# OR1 (OpenRule1um) technology LEF
# Aligned to drawn cell library: ML1-ML3 width 1.0, space relaxed to 0.5
# (cells are drawn with 0.5um internal spacing; canonical 1.0um space
#  is unsatisfiable against this library)
# Grid pitch 2.0um for ML1 (H), ML2 (V), ML3 (H)
VERSION 5.4 ;
NAMESCASESENSITIVE ON ;
BUSBITCHARS "[]" ;
DIVIDERCHAR "/" ;
UNITS
  DATABASE MICRONS 1000 ;
END UNITS

MANUFACTURINGGRID 0.1 ;







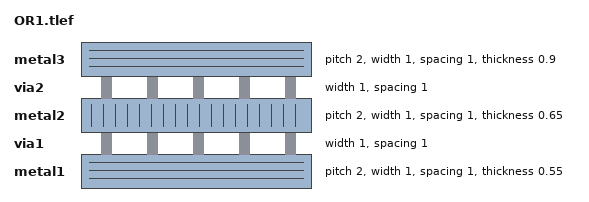
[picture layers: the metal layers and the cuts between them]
LAYER metal1
  TYPE		ROUTING ;
  DIRECTION	HORIZONTAL ;
  PITCH		2.0 ;
  OFFSET	1.0 ;
  WIDTH		1.0 ;
  SPACING	1.0 ;
  THICKNESS	0.55 ;
  RESISTANCE	RPERSQ 0.0509 ;
  CAPACITANCE	CPERSQDIST 3.5e-05 ;
END metal1

LAYER via1
  TYPE	CUT ;
  WIDTH		1.0 ;
  SPACING	1.0 ;
END via1

LAYER metal2
  TYPE		ROUTING ;
  DIRECTION	VERTICAL ;
  PITCH		2.0 ;
  OFFSET	1.0 ;
  WIDTH		1.0 ;
  SPACING	1.0 ;
  THICKNESS	0.65 ;
  RESISTANCE	RPERSQ 0.0431 ;
  CAPACITANCE	CPERSQDIST 3.5e-05 ;
END metal2

LAYER via2
  TYPE	CUT ;
  WIDTH		1.0 ;
  SPACING	1.0 ;
END via2

LAYER metal3
  TYPE		ROUTING ;
  DIRECTION	HORIZONTAL ;
  PITCH		2.0 ;
  OFFSET	1.0 ;
  WIDTH		1.0 ;
  SPACING	1.0 ;
  THICKNESS	0.90 ;
  RESISTANCE	RPERSQ 0.0311 ;
  CAPACITANCE	CPERSQDIST 3.5e-05 ;
END metal3



VIA M2_M1 DEFAULT
  LAYER metal1 ;
    RECT -1.000 -1.000 1.000 1.000 ;
  LAYER via1 ;
    RECT -0.500 -0.500 0.500 0.500 ;
  LAYER metal2 ;
    RECT -1.000 -1.000 1.000 1.000 ;
END M2_M1

VIA M3_M2 DEFAULT
  LAYER metal2 ;
    RECT -1.000 -1.000 1.000 1.000 ;
  LAYER via2 ;
    RECT -0.500 -0.500 0.500 0.500 ;
  LAYER metal3 ;
    RECT -1.000 -1.000 1.000 1.000 ;
END M3_M2

SITE unit
  CLASS CORE ;
  SYMMETRY Y ;
  SIZE 0.500 BY 30.000 ;
END unit

SITE core
  CLASS CORE ;
  SYMMETRY X Y ;
  SIZE 0.500 BY 30.000 ;
END core

END LIBRARY
